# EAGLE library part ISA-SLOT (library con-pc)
ISA SLOT

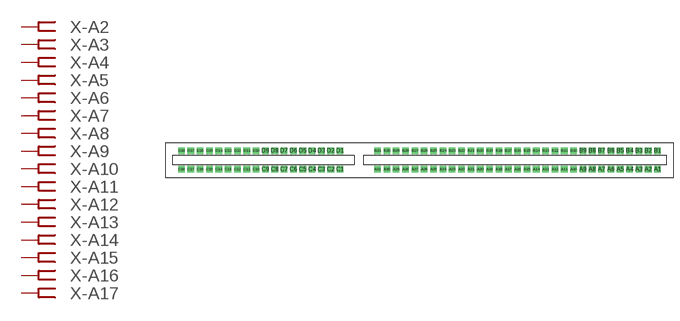
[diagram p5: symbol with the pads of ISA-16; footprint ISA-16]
Designator prefix X; gates -A2=FEMREC -A3=FEMREC -A4=FEMREC -A5=FEMREC -A6=FEMREC -A7=FEMREC -A8=FEMREC -A9=FEMREC -A10=FEMREC -A11=FEMREC -A12=FEMREC -A13=FEMREC -A14=FEMREC -A15=FEMREC -A16=FEMREC -A17=FEMREC -A18=FEMREC -A19=FEMREC -A20=FEMREC -A21=FEMREC -A22=FEMREC -A23=FEMREC -A24=FEMREC -A25=FEMREC -A26=FEMREC -A27=FEMREC -A28=FEMREC -A29=FEMREC -A30=FEMREC -A31=FEMREC -B2=FEMREC -B3=FEMREC -B4=FEMREC -B5=FEMREC -B6=FEMREC -B7=FEMREC -B8=FEMREC -B9=FEMREC -B10=FEMREC -B11=FEMREC -B12=FEMREC -B13=FEMREC -B14=FEMREC -B15=FEMREC -B16=FEMREC -B17=FEMREC -B18=FEMREC -B19=FEMREC -B20=FEMREC -B21=FEMREC -B22=FEMREC -B23=FEMREC -B24=FEMREC -B25=FEMREC -B26=FEMREC -B27=FEMREC -B28=FEMREC -B29=FEMREC -B30=FEMREC -B31=FEMREC -C2=FEMREC -C3=FEMREC -C4=FEMREC -C5=FEMREC -C6=FEMREC -C7=FEMREC -C8=FEMREC -C9=FEMREC -C10=FEMREC -C11=FEMREC -C12=FEMREC -C13=FEMREC -C14=FEMREC -C15=FEMREC -C16=FEMREC -C17=FEMREC -C18=FEMREC -D2=FEMREC -D3=FEMREC -D4=FEMREC -D5=FEMREC -D6=FEMREC -D7=FEMREC -D8=FEMREC -D9=FEMREC -D10=FEMREC -D11=FEMREC -D12=FEMREC -D13=FEMREC -D14=FEMREC -D15=FEMREC -D16=FEMREC -D17=FEMREC -D18=FEMREC -A1=FEMRVAL -B1=FEMRVAL -C1=FEMRVAL -D1=FEMRVAL

## ISA-SLOT  [ISA-16]
A1  -A1:P  pas
A2  -A2:P  pas
A3  -A3:P  pas
A4  -A4:P  pas
A5  -A5:P  pas
A6  -A6:P  pas
A7  -A7:P  pas
A8  -A8:P  pas
A9  -A9:P  pas
A10  -A10:P  pas
A11  -A11:P  pas
A12  -A12:P  pas
A13  -A13:P  pas
A14  -A14:P  pas
A15  -A15:P  pas
A16  -A16:P  pas
A17  -A17:P  pas
A18  -A18:P  pas
A19  -A19:P  pas
A20  -A20:P  pas
A21  -A21:P  pas
A22  -A22:P  pas
A23  -A23:P  pas
A24  -A24:P  pas
A25  -A25:P  pas
A26  -A26:P  pas
A27  -A27:P  pas
A28  -A28:P  pas
A29  -A29:P  pas
A30  -A30:P  pas
A31  -A31:P  pas
B1  -B1:P  pas
B2  -B2:P  pas
B3  -B3:P  pas
B4  -B4:P  pas
B5  -B5:P  pas
B6  -B6:P  pas
B7  -B7:P  pas
B8  -B8:P  pas
B9  -B9:P  pas
B10  -B10:P  pas
B11  -B11:P  pas
B12  -B12:P  pas
B13  -B13:P  pas
B14  -B14:P  pas
B15  -B15:P  pas
B16  -B16:P  pas
B17  -B17:P  pas
B18  -B18:P  pas
B19  -B19:P  pas
B20  -B20:P  pas
B21  -B21:P  pas
B22  -B22:P  pas
B23  -B23:P  pas
B24  -B24:P  pas
B25  -B25:P  pas
B26  -B26:P  pas
B27  -B27:P  pas
B28  -B28:P  pas
B29  -B29:P  pas
B30  -B30:P  pas
B31  -B31:P  pas
C1  -C1:P  pas
C2  -C2:P  pas
C3  -C3:P  pas
C4  -C4:P  pas
C5  -C5:P  pas
C6  -C6:P  pas
C7  -C7:P  pas
C8  -C8:P  pas
C9  -C9:P  pas
C10  -C10:P  pas
C11  -C11:P  pas
C12  -C12:P  pas
C13  -C13:P  pas
C14  -C14:P  pas
C15  -C15:P  pas
C16  -C16:P  pas
C17  -C17:P  pas
C18  -C18:P  pas
D1  -D1:P  pas
D2  -D2:P  pas
D3  -D3:P  pas
D4  -D4:P  pas
D5  -D5:P  pas
D6  -D6:P  pas
D7  -D7:P  pas
D8  -D8:P  pas
D9  -D9:P  pas
D10  -D10:P  pas
D11  -D11:P  pas
D12  -D12:P  pas
D13  -D13:P  pas
D14  -D14:P  pas
D15  -D15:P  pas
D16  -D16:P  pas
D17  -D17:P  pas
D18  -D18:P  pas

## Footprint ISA-16 (pad centres in mm)
ISA SLOT
drill 1.2 pad 1.778 square: A1 81.28,-2.54; A2 78.74,-2.54; A3 76.2,-2.54; A4 73.66,-2.54; A5 71.12,-2.54; A6 68.58,-2.54; A7 66.04,-2.54; A8 63.5,-2.54; A9 60.96,-2.54; A10 58.42,-2.54; A11 55.88,-2.54; A12 53.34,-2.54; A13 50.8,-2.54; A14 48.26,-2.54; A15 45.72,-2.54; A16 43.18,-2.54; A17 40.64,-2.54; A18 38.1,-2.54; A19 35.56,-2.54; A20 33.02,-2.54; A21 30.48,-2.54; A22 27.94,-2.54; A23 25.4,-2.54; A24 22.86,-2.54; A25 20.32,-2.54; A26 17.78,-2.54; A27 15.24,-2.54; A28 12.7,-2.54; A29 10.16,-2.54; A30 7.62,-2.54; A31 5.08,-2.54; B1 81.28,2.54; B2 78.74,2.54; B3 76.2,2.54; B4 73.66,2.54; B5 71.12,2.54; B6 68.58,2.54; B7 66.04,2.54; B8 63.5,2.54; B9 60.96,2.54; B10 58.42,2.54; B11 55.88,2.54; B12 53.34,2.54; B13 50.8,2.54; B14 48.26,2.54; B15 45.72,2.54; B16 43.18,2.54; B17 40.64,2.54; B18 38.1,2.54; B19 35.56,2.54; B20 33.02,2.54; B21 30.48,2.54; B22 27.94,2.54; B23 25.4,2.54; B24 22.86,2.54; B25 20.32,2.54; B26 17.78,2.54; B27 15.24,2.54; B28 12.7,2.54; B29 10.16,2.54; B30 7.62,2.54; B31 5.08,2.54; C1 -5.08,-2.54; C2 -7.62,-2.54; C3 -10.16,-2.54; C4 -12.7,-2.54; C5 -15.24,-2.54; C6 -17.78,-2.54; C7 -20.32,-2.54; C8 -22.86,-2.54; C9 -25.4,-2.54; C10 -27.94,-2.54; C11 -30.48,-2.54; C12 -33.02,-2.54; C13 -35.56,-2.54; C14 -38.1,-2.54; C15 -40.64,-2.54; C16 -43.18,-2.54; C17 -45.72,-2.54; C18 -48.26,-2.54; D1 -5.08,2.54; D2 -7.62,2.54; D3 -10.16,2.54; D4 -12.7,2.54; D5 -15.24,2.54; D6 -17.78,2.54; D7 -20.32,2.54; D8 -22.86,2.54; D9 -25.4,2.54; D10 -27.94,2.54; D11 -30.48,2.54; D12 -33.02,2.54; D13 -35.56,2.54; D14 -38.1,2.54; D15 -40.64,2.54; D16 -43.18,2.54; D17 -45.72,2.54; D18 -48.26,2.54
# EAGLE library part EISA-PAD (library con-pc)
EISA CARD CONNECTOR

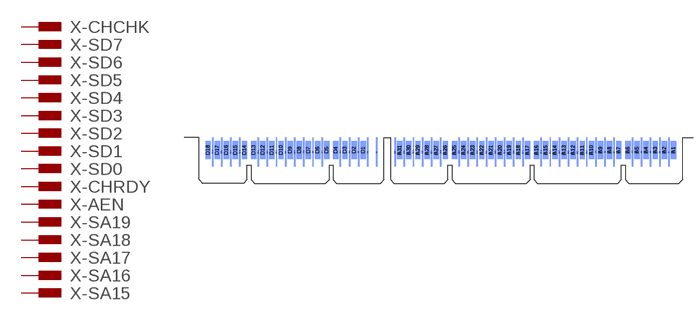
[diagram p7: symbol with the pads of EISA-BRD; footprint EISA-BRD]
Designator prefix X; gates -CHCHK=MALE -SD7=MALE -SD6=MALE -SD5=MALE -SD4=MALE -SD3=MALE -SD2=MALE -SD1=MALE -SD0=MALE -CHRDY=MALE -AEN=MALE -SA19=MALE -SA18=MALE -SA17=MALE -SA16=MALE -SA15=MALE -SA14=MALE -SA13=MALE -SA12=MALE -SA11=MALE -SA10=MALE -SA9=MALE -SA8=MALE -SA7=MALE -SA6=MALE -SA5=MALE -SA4=MALE -SA3=MALE -SA2=MALE -SA1=MALE -SA0=MALE GND11=GND -RESV10=MALE +5V5=+5V -IRQ2=MALE -5V0=-5V -DRQ2=MALE -12V0=-12V -NOWS=MALE +12V0=+12V GND12=GND -SMWTC=MALE -SMRDC=MALE -IOWC=MALE -IORC=MALE -DAK3=MALE -DRQ3=MALE -DAK1=MALE -DRQ1=MALE -REFRESH=MALE -BLCK=MALE -IRQ7=MALE -IRQ6=MALE -IRQ5=MALE -IRQ4=MALE -IRQ3=MALE -DAK2=MALE -TC=MALE -BALE=MALE +5V6=+5V -OSC=MALE GND13=GND -CMD=MALE -START=MALE -EXRDY=MALE -EX32=MALE GND0=GND -EX16=MALE -SLBURST=MALE -MSBURST=MALE -W/R=MALE GND1=GND -RESERV1=RESERV -RESERV2=RESERV -RESERV3=RESERV GND2=GND -BE1=MALE -LA31=MALE GND3=GND -LA30=MALE -LA28=MALE -LA27=MALE -LA25=MALE GND4=GND -LA15=MALE -LA13=MALE -LA12=MALE -LA11=MALE GND5=GND -LA9=MALE GND6=GND +5V0=+5V +5V1=+5V -RESERV4=RESERV -RESERV5=RESERV -RESERV6=RESERV -RESERV7=RESERV +12V=+12V -M/IO=MALE -LOCK=MALE -RESERV8=RESERV GND7=GND -RESERV9=RESERV -BE3=MALE -BE2=MALE -BE0=MALE GND8=GND +5V2=+5V -LA29=MALE GND9=GND -LA26=MALE -LA24=MALE -LA16=MALE -LA14=MALE +5V3=+5V +5V4=+5V GND10=GND -LA10=MALE -SBHE=MALE -LA23=MALE -LA22=MALE -LA21=MALE -LA20=MALE -LA19=MALE -LA18=MALE -LA17=MALE -MRDC=MALE -MWTC=MALE -SD8=MALE -SD9=MALE -SD10=MALE -SD11=MALE -SD12=MALE -SD13=MALE -SD14=MALE -SD15=MALE -M16=MALE -IO16=MALE -IRQ10=MALE -IRQ11=MALE -IRQ12=MALE -IRQ13=MALE -IRQ14=MALE -DAK0=MALE -DRQ0=MALE -DAK5=MALE -DRQ5=MALE -DAK6=MALE -DRQ6=MALE -DAK7=MALE -DRQ7=MALE +5V10=+5V MASTER16=MALE GND20=GND -LA7=MALE GND14=GND -LA4=MALE -LA3=MALE GND15=GND -SD17=MALE -SD19=MALE -SD20=MALE -SD22=MALE GND16=GND -SD25=MALE -SD26=MALE -SD28=MALE GND17=GND -SD30=MALE -SD31=MALE -MREQX=MALE -LA8=MALE -LA6=MALE -LA5=MALE +5V7=+5V -LA2=MALE -SD16=MALE -SD18=MALE GND18=GND -SD21=MALE -SD23=MALE -SD24=MALE GND19=GND -SD27=MALE -SD29=MALE +5V8=+5V +5V9=+5V -MAKX=MALE

## EISA-PAD  [EISA-BRD]
A1  -CHCHK:P  pas
A2  -SD7:P  pas
A3  -SD6:P  pas
A4  -SD5:P  pas
A5  -SD4:P  pas
A6  -SD3:P  pas
A7  -SD2:P  pas
A8  -SD1:P  pas
A9  -SD0:P  pas
A10  -CHRDY:P  pas
A11  -AEN:P  pas
A12  -SA19:P  pas
A13  -SA18:P  pas
A14  -SA17:P  pas
A15  -SA16:P  pas
A16  -SA15:P  pas
A17  -SA14:P  pas
A18  -SA13:P  pas
A19  -SA12:P  pas
A20  -SA11:P  pas
A21  -SA10:P  pas
A22  -SA9:P  pas
A23  -SA8:P  pas
A24  -SA7:P  pas
A25  -SA6:P  pas
A26  -SA5:P  pas
A27  -SA4:P  pas
A28  -SA3:P  pas
A29  -SA2:P  pas
A30  -SA1:P  pas
A31  -SA0:P  pas
B1  GND11:GND  pwr
B2  -RESV10:P  pas
B3  +5V5:+5V  pwr
B4  -IRQ2:P  pas
B5  -5V0:-5V  pwr
B6  -DRQ2:P  pas
B7  -12V0:-12V  pwr
B8  -NOWS:P  pas
B9  +12V0:+12V  pwr
B10  GND12:GND  pwr
B11  -SMWTC:P  pas
B12  -SMRDC:P  pas
B13  -IOWC:P  pas
B14  -IORC:P  pas
B15  -DAK3:P  pas
B16  -DRQ3:P  pas
B17  -DAK1:P  pas
B18  -DRQ1:P  pas
B19  -REFRESH:P  pas
B20  -BLCK:P  pas
B21  -IRQ7:P  pas
B22  -IRQ6:P  pas
B23  -IRQ5:P  pas
B24  -IRQ4:P  pas
B25  -IRQ3:P  pas
B26  -DAK2:P  pas
B27  -TC:P  pas
B28  -BALE:P  pas
B29  +5V6:+5V  pwr
B30  -OSC:P  pas
B31  GND13:GND  pwr
C1  -SBHE:P  pas
C2  -LA23:P  pas
C3  -LA22:P  pas
C4  -LA21:P  pas
C5  -LA20:P  pas
C6  -LA19:P  pas
C7  -LA18:P  pas
C8  -LA17:P  pas
C9  -MRDC:P  pas
C10  -MWTC:P  pas
C11  -SD8:P  pas
C12  -SD9:P  pas
C13  -SD10:P  pas
C14  -SD11:P  pas
C15  -SD12:P  pas
C16  -SD13:P  pas
C17  -SD14:P  pas
C18  -SD15:P  pas
D1  -M16:P  pas
D2  -IO16:P  pas
D3  -IRQ10:P  pas
D4  -IRQ11:P  pas
D5  -IRQ12:P  pas
D6  -IRQ13:P  pas
D7  -IRQ14:P  pas
D8  -DAK0:P  pas
D9  -DRQ0:P  pas
D10  -DAK5:P  pas
D11  -DRQ5:P  pas
D12  -DAK6:P  pas
D13  -DRQ6:P  pas
D14  -DAK7:P  pas
D15  -DRQ7:P  pas
D16  +5V10:+5V  pwr
D17  MASTER16:P  pas
D18  GND20:GND  pwr
E1  -CMD:P  pas
E2  -START:P  pas
E3  -EXRDY:P  pas
E4  -EX32:P  pas
E5  GND0:GND  pwr
E7  -EX16:P  pas
E8  -SLBURST:P  pas
E9  -MSBURST:P  pas
E10  -W/R:P  pas
E11  GND1:GND  pwr
E12  -RESERV1:RSV  pas
E13  -RESERV2:RSV  pas
E14  -RESERV3:RSV  pas
E15  GND2:GND  pwr
E17  -BE1:P  pas
E18  -LA31:P  pas
E19  GND3:GND  pwr
E20  -LA30:P  pas
E21  -LA28:P  pas
E22  -LA27:P  pas
E23  -LA25:P  pas
E24  GND4:GND  pwr
E26  -LA15:P  pas
E27  -LA13:P  pas
E28  -LA12:P  pas
E29  -LA11:P  pas
E30  GND5:GND  pwr
E31  -LA9:P  pas
F1  GND6:GND  pwr
F2  +5V0:+5V  pwr
F3  +5V1:+5V  pwr
F4  -RESERV4:RSV  pas
F5  -RESERV5:RSV  pas
F7  -RESERV6:RSV  pas
F8  -RESERV7:RSV  pas
F9  +12V:+12V  pwr
F10  -M/IO:P  pas
F11  -LOCK:P  pas
F12  -RESERV8:RSV  pas
F13  GND7:GND  pwr
F14  -RESERV9:RSV  pas
F15  -BE3:P  pas
F17  -BE2:P  pas
F18  -BE0:P  pas
F19  GND8:GND  pwr
F20  +5V2:+5V  pwr
F21  -LA29:P  pas
F22  GND9:GND  pwr
F23  -LA26:P  pas
F24  -LA24:P  pas
F26  -LA16:P  pas
F27  -LA14:P  pas
F28  +5V3:+5V  pwr
F29  +5V4:+5V  pwr
F30  GND10:GND  pwr
F31  -LA10:P  pas
G1  -LA7:P  pas
G2  GND14:GND  pwr
G3  -LA4:P  pas
G4  -LA3:P  pas
G5  GND15:GND  pwr
G7  -SD17:P  pas
G8  -SD19:P  pas
G9  -SD20:P  pas
G10  -SD22:P  pas
G11  GND16:GND  pwr
G12  -SD25:P  pas
G13  -SD26:P  pas
G14  -SD28:P  pas
G16  GND17:GND  pwr
G17  -SD30:P  pas
G18  -SD31:P  pas
G19  -MREQX:P  pas
H1  -LA8:P  pas
H2  -LA6:P  pas
H3  -LA5:P  pas
H4  +5V7:+5V  pwr
H5  -LA2:P  pas
H7  -SD16:P  pas
H8  -SD18:P  pas
H9  GND18:GND  pwr
H10  -SD21:P  pas
H11  -SD23:P  pas
H12  -SD24:P  pas
H13  GND19:GND  pwr
H14  -SD27:P  pas
H16  -SD29:P  pas
H17  +5V8:+5V  pwr
H18  +5V9:+5V  pwr
H19  -MAKX:P  pas

## Footprint EISA-BRD (pad centres in mm)
EISA CARD CONNECTOR
smd 1.5 x 5: A1 79.65,9.204; A2 77.11,9.204; A3 74.57,9.204; A4 72.03,9.204; A5 69.49,9.204; A6 66.95,9.204; A7 64.41,9.204; A8 61.87,9.204; A9 59.33,9.204; A10 56.79,9.204; A11 54.25,9.204; A12 51.71,9.204; A13 49.17,9.204; A14 46.63,9.204; A15 44.09,9.204; A16 41.55,9.204; A17 39.01,9.204; A18 36.47,9.204; A19 33.93,9.204; A20 31.39,9.204; A21 28.85,9.204; A22 26.31,9.204; A23 23.77,9.204; A24 21.23,9.204; A25 18.69,9.204; A26 16.15,9.204; A27 13.61,9.204; A28 11.07,9.204; A29 8.53,9.204; A30 5.99,9.204; A31 3.45,9.204; C1 -6.71,9.204; C2 -9.25,9.204; C3 -11.79,9.204; C4 -14.33,9.204; C5 -16.87,9.204; C6 -19.41,9.204; C7 -21.95,9.204; C8 -24.49,9.204; C9 -27.03,9.204; C10 -29.57,9.204; C11 -32.11,9.204; C12 -34.65,9.204; C13 -37.19,9.204; C14 -39.73,9.204; C15 -42.27,9.204; C16 -44.81,9.204; C17 -47.35,9.204; C18 -49.89,9.204
smd 1.5 x 5 bottom: B1 79.65,9.204; B2 77.11,9.204; B3 74.57,9.204; B4 72.03,9.204; B5 69.49,9.204; B6 66.95,9.204; B7 64.41,9.204; B8 61.87,9.204; B9 59.33,9.204; B10 56.79,9.204; B11 54.25,9.204; B12 51.71,9.204; B13 49.17,9.204; B14 46.63,9.204; B15 44.09,9.204; B16 41.55,9.204; B17 39.01,9.204; B18 36.47,9.204; B19 33.93,9.204; B20 31.39,9.204; B21 28.85,9.204; B22 26.31,9.204; B23 23.77,9.204; B24 21.23,9.204; B25 18.69,9.204; B26 16.15,9.204; B27 13.61,9.204; B28 11.07,9.204; B29 8.53,9.204; B30 5.99,9.204; B31 3.45,9.204; D1 -6.71,9.204; D2 -9.25,9.204; D3 -11.79,9.204; D4 -14.33,9.204; D5 -16.87,9.204; D6 -19.41,9.204; D7 -21.95,9.204; D8 -24.49,9.204; D9 -27.03,9.204; D10 -29.57,9.204; D11 -32.11,9.204; D12 -34.65,9.204; D13 -37.19,9.204; D14 -39.73,9.204; D15 -42.27,9.204; D16 -44.81,9.204; D17 -47.35,9.204; D18 -49.89,9.204
smd 0.4 x 8: E1 78.38,8.697; E2 75.84,8.697; E3 73.3,8.697; E4 70.76,8.697; E5 68.22,8.697; E7 63.14,8.697; E8 60.6,8.697; E9 58.06,8.697; E10 55.52,8.697; E11 52.98,8.697; E12 50.44,8.697; E13 47.9,8.697; E14 45.36,8.697; E15 42.82,8.697; E17 37.74,8.697; E18 35.2,8.697; E19 32.66,8.697; E20 30.12,8.697; E21 27.58,8.697; E22 25.04,8.697; E23 22.5,8.697; E24 19.96,8.697; E26 14.88,8.697; E27 12.34,8.697; E28 9.8,8.697; E29 7.26,8.697; E30 4.72,8.697; E31 2.18,8.697; G1 -2.9,8.697; G2 -5.44,8.697; G3 -7.98,8.697; G4 -10.52,8.697; G5 -13.06,8.697; G7 -18.14,8.697; G8 -20.68,8.697; G9 -23.22,8.697; G10 -25.76,8.697; G11 -28.3,8.697; G12 -30.84,8.697; G13 -33.38,8.697; G14 -35.92,8.697; G16 -41,8.697; G17 -43.54,8.697; G18 -46.08,8.697; G19 -48.62,8.697
smd 0.4 x 8 bottom: F1 78.38,8.697; F2 75.84,8.697; F3 73.3,8.697; F4 70.76,8.697; F5 68.22,8.697; F7 63.14,8.697; F8 60.6,8.697; F9 58.06,8.697; F10 55.52,8.697; F11 52.98,8.697; F12 50.44,8.697; F13 47.9,8.697; F14 45.36,8.697; F15 42.82,8.697; F17 37.74,8.697; F18 35.2,8.697; F19 32.66,8.697; F20 30.12,8.697; F21 27.58,8.697; F22 25.04,8.697; F23 22.5,8.697; F24 19.96,8.697; F26 14.88,8.697; F27 12.34,8.697; F28 9.8,8.697; F29 7.26,8.697; F30 4.72,8.697; F31 2.18,8.697; H1 -2.9,8.697; H2 -5.44,8.697; H3 -7.98,8.697; H4 -10.52,8.697; H5 -13.06,8.697; H7 -18.14,8.697; H8 -20.68,8.697; H9 -23.22,8.697; H10 -25.76,8.697; H11 -28.3,8.697; H12 -30.84,8.697; H13 -33.38,8.697; H14 -35.92,8.697; H16 -41,8.697; H17 -43.54,8.697; H18 -46.08,8.697; H19 -48.62,8.697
